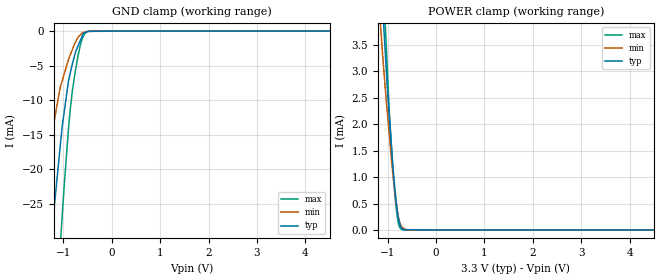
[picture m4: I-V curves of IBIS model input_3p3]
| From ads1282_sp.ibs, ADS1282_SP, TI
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|   input_3p3 Model
[Model]   input_3p3
Model_type   Input
Vinl = 0.66
Vinh = 2.64
|   typ   min   max
|   (nom PVT)   (Fast PVT)   (slow PVT)
|C_comp from frequency sweep method(F=4.1MHz)
|C_comp   3.666e-12   3.075e-12   4.204e-12
|C_comp from LC tank measurement(L=1nH)
|Resonant Frequency(Hz)   3.440e+09   3.460e+09   3.410e+09
C_comp   2.143e-12   2.118e-12   2.181e-12
| Where nom  PVT is Nominal Process,  3.3V,  25C
|   Fast PVT is Strong Process,   3.6V,  -40C
|   Slow PVT is Weak Process,   3V,  85C
[Model Spec]
Vinl   0.66   0.6   0.72
Vinh   2.64   2.4   2.88
[Voltage Range]   3.3   3   3.6
|Ambient Temperature   25   85   -40
|Junction Temperature
[Temperature Range]   25   85   -40
[Power Clamp Reference]   3.3   3   3.6
[GND Clamp Reference]   0   0   0
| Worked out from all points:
|   GND clamp passes 1 mA (typ) near -0.63 V on its own axis
|   POWER clamp passes 1 mA (typ) near -0.87 V on its own axis
[GND Clamp]
|   Voltage   I(typ)   I(min)   I(max)
-3.3V     -244.7mA   -167.1mA   -315mA
-1.617V   -63.98mA   -35.61mA   -98.6mA
-1.461V   -49.16mA   -26.24mA   -78.79mA
-1.245V   -30.03mA   -15.1mA    -52.22mA
-1.068V   -16.67mA   -8.14mA    -31.19mA
-1.03V    -13.93mA   -7.236mA   -26.98mA
-896.4mV  -7.217mA   -4.104mA   -14.12mA
-820.8mV  -4.87mA    -2.728mA   -8.903mA
-694.8mV  -2.061mA   -830.2uA   -3.406mA
-591mV    -373.4uA   -191.4uA   -745.7uA
-360mV    -37.09uA   -943.8nA   -522.5nA
6.6V      0A         0A         0A
[POWER Clamp]
|   Voltage   I(typ)   I(min)   I(max)
-3.3V     49.8mA     41.86mA    60.27mA
-1.152V   5.087mA    3.908mA    6.196mA
-1.089V   3.963mA    3.12mA     4.771mA
-1.048V   3.312mA    2.646mA    3.839mA
-1.035V   3.114mA    2.502mA    3.589mA
-968.4mV  2.164mA    1.821mA    2.266mA
-896.4mV  1.255mA    1.086mA    1.175mA
-871.2mV  980.7uA    879.6uA    875.5uA
-792mV    301uA      312uA      187.9uA
-712.8mV  32.54uA    63.77uA    8.168uA
-591mV    5.585uA    2.067uA    189.7nA
6.6V      0A         0A         0A
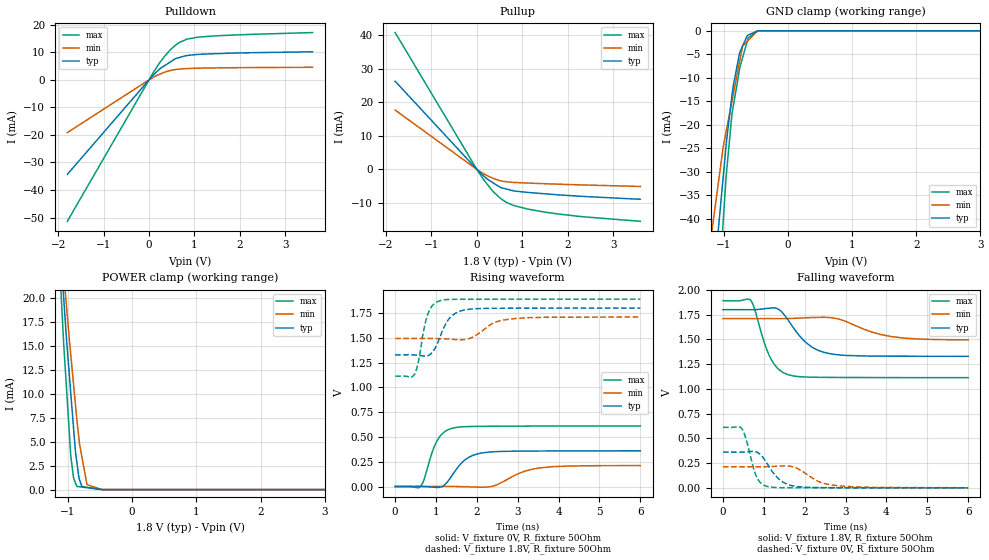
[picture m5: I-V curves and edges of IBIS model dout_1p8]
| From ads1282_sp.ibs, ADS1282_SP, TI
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|   dout_1p8 Model
[Model]   dout_1p8
Model_type   3-state
Polarity   Non-Inverting
Vmeas = 0.9
Vref = 0.9
Cref = 20pF
Rref = 50
|   typ   min   max
|   (nom PVT)   (Fast PVT)   (slow PVT)
|C_comp from frequency sweep method(F=4.1MHz)
C_comp   4.866e-12   3.817e-12   5.969e-12
|ON state : BUFFER OUTPUT TURNED HIGH
|C_comp   4.866e-12   3.817e-12   5.969e-12
|OFF state: BUFFER IN HIGH IMPEDANCE
|C_comp   4.612e-12   3.553e-12   5.679e-12
|C_comp from LC tank measurement(L=1nH)
|Resonant Frequency(Hz)   3.060e+09   3.240e+09   2.860e+09
|C_comp   2.708e-12   2.415e-12   3.100e-12
|ON state : BUFFER OUTPUT TURNED HIGH
|Resonant Frequency(Hz)   3.060e+09   3.240e+09   2.860e+09
|C_comp   2.708e-12   2.415e-12   3.100e-12
|OFF state: BUFFER IN HIGH IMPEDANCE
|Resonant Frequency(Hz)   3.100e+09   3.340e+09   2.870e+09
|C_comp   2.638e-12   2.273e-12   3.078e-12
| Where nom  PVT is Nominal Process,  1.8V,  25C
|   Fast PVT is Strong Process,   1.89V,  -40C
|   Slow PVT is Weak Process,   1.71V,  85C
[Voltage Range]   1.8   1.71   1.89
|Ambient Temperature   25   85   -40
|Junction Temperature
[Temperature Range]   25   85   -40
[Pullup Reference]   1.8   1.71   1.89
[Pulldown Reference]   0   0   0
[Power Clamp Reference]   1.8   1.71   1.89
[GND Clamp Reference]   0   0   0
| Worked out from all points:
|   slope of the pulldown table from 0 to 0.27 V, typ, clamps not added: 61.6 ohm
|   slope of the pullup table from 0 to 0.27 V, typ, clamps not added: 82.6 ohm
|   GND clamp passes 1 mA (typ) near -0.63 V on its own axis
|   POWER clamp passes 1 mA (typ) near -0.82 V on its own axis
|   falling waveform, V_fixture 1.8V, R_fixture 50Ohm: 20-80 % time 599ps typ, 910ps min, 397ps max; typ from 1.8 V to 1.33 V
|   rising waveform, V_fixture 0V, R_fixture 50Ohm: 20-80 % time 452ps typ, 686ps min, 321ps max; typ from 0 V to 0.36 V
|   rising waveform, V_fixture 1.8V, R_fixture 50Ohm: 20-80 % time 338ps typ, 497ps min, 222ps max; typ from 1.33 V to 1.8 V
|   falling waveform, V_fixture 0V, R_fixture 50Ohm: 20-80 % time 411ps typ, 556ps min, 244ps max; typ from 0.361 V to 0.001 V
[Pulldown]
|   Voltage   I(typ)   I(min)   I(max)
-1.8V     -34.32mA   -19.15mA   -51.35mA
107.7mV   1.937mA    1.049mA    3.036mA
252mV     4.192mA    2.177mA    6.588mA
332.6mV   5.052mA    2.713mA    8.353mA
451.7mV   6.321mA    3.316mA    10.59mA
574.6mV   7.631mA    3.732mA    12.46mA
667.2mV   8.107mA    3.886mA    13.56mA
835.4mV   8.812mA    4.089mA    14.78mA
1.089V    9.234mA    4.225mA    15.5mA
1.784V    9.681mA    4.391mA    16.21mA
3.6V      10.18mA    4.555mA    17.16mA
[GND Clamp]
|   Voltage   I(typ)   I(min)   I(max)
-1.8V     -174.4mA   -116.1mA   -255.2mA
-1.228V   -66.8mA    -47.38mA   -96.3mA
-1.105V   -45.8mA    -34.84mA   -64.56mA
-1.07V    -40.56mA   -31.23mA   -55.44mA
-1.005V   -31.06mA   -24.69mA   -40.45mA
-958.2mV  -24.08mA   -21.3mA    -30.74mA
-869.4mV  -13.74mA   -14.98mA   -17.71mA
-750.6mV  -4.735mA   -6.531mA   -8.173mA
-704.5mV  -3.283mA   -3.252mA   -5.744mA
-630mV    -987.2uA   -2.225mA   -2.174mA
-458.3mV  -20.05uA   -17.99uA   -22.38uA
3.6V      0A         0A         0A
[Pullup]
|   Voltage   I(typ)   I(min)   I(max)
-1.8V     26.3mA     17.69mA    40.8mA
0V        0A         0A         0A
139.9mV   -1.835mA   -1.206mA   -2.9mA
332.6mV   -3.8mA     -2.5mA     -6.214mA
502.7mV   -5.226mA   -3.313mA   -8.442mA
655.8mV   -5.863mA   -3.676mA   -9.859mA
801.4mV   -6.358mA   -3.868mA   -10.71mA
1.382V    -7.135mA   -4.203mA   -12.47mA
2.268V    -7.992mA   -4.603mA   -14.02mA
3.6V      -8.89mA    -5.079mA   -15.46mA
[POWER Clamp]
|   Voltage   I(typ)   I(min)   I(max)
-1.8V     87.36mA    77.13mA    101.7mA
-1.365V   49.31mA    46mA       53.95mA
-1.066V   20.03mA    22.59mA    15.23mA
-1.019V   15.4mA     18.9mA     10.24mA
-952.6mV  9.818mA    13.86mA    3.343mA
-912.9mV  6.472mA    11.02mA    1.23mA
-861.8mV  2.905mA    7.378mA    329.9uA
-820.8mV  1.04mA     4.853mA    295.3uA
-781.2mV  314.7uA    3.375mA    261.9uA
-702.8mV  235uA      516.8uA    195.8uA
-470.3mV  26.54nA    462.1nA    2.631nA
3.6V      0A         0A         0A
[Ramp]
R_load = 50
|   typ   min   max
dV/dt_r   0.215956/4.48764e-10   0.126791/6.81913e-10   0.366527/3.20304e-10
dV/dt_f   0.282717/5.98615e-10   0.129101/8.95175e-10   0.466066/3.95416e-10
[Falling Waveform]
V_fixture = 1.8V
V_fixture_min = 1.71V
V_fixture_max = 1.89V
R_fixture = 50Ohm
|   Time   V(typ)   V(min)   V(max)
0s        1.8V       1.71V      1.89V
670ps     1.799V     1.71V      1.899V
770ps     1.8V       1.71V      1.813V
1.162ns   1.816V     1.71V      1.313V
1.356ns   1.804V     1.71V      1.2V
1.6ns     1.691V     1.71V      1.143V
2.052ns   1.46V      1.718V     1.119V
2.602ns   1.357V     1.721V     1.116V
4.1ns     1.33V      1.529V     1.114V
6ns       1.329V     1.495V     1.113V
[Rising Waveform]
V_fixture = 0V
V_fixture_min = 0V
V_fixture_max = 0V
R_fixture = 50Ohm
|   Time   V(typ)   V(min)   V(max)
0s        552.4pV    690.8pV    457.1pV
618ps     548.2uV    14.16uV    1.117mV
700ps     103.6uV    41.05uV    61.6mV
1.026ns   -10.17mV   243.7uV    461.5mV
1.206ns   15.09mV    378.1uV    550.9mV
1.426ns   132.2mV    325.7uV    590mV
1.81ns    296.4mV    -3.345mV   604.9mV
2.248ns   345mV      -5.814mV   607.4mV
3.528ns   358mV      187.2mV    609.7mV
6ns       359.9mV    211.3mV    610.9mV
[Rising Waveform]
V_fixture = 1.8V
V_fixture_min = 1.71V
V_fixture_max = 1.89V
R_fixture = 50Ohm
|   Time   V(typ)   V(min)   V(max)
0s        1.328V     1.493V     1.113V
472ps     1.327V     1.493V     1.128V
566ps     1.323V     1.493V     1.253V
792ps     1.317V     1.493V     1.731V
1.096ns   1.504V     1.491V     1.874V
1.382ns   1.72V      1.485V     1.888V
1.756ns   1.785V     1.485V     1.888V
2.422ns   1.798V     1.652V     1.889V
2.928ns   1.798V     1.694V     1.889V
6ns       1.8V       1.709V     1.89V
[Falling Waveform]
V_fixture = 0V
V_fixture_min = 0V
V_fixture_max = 0V
R_fixture = 50Ohm
|   Time   V(typ)   V(min)   V(max)
0s        361.1mV    213.1mV    611.1mV
472ps     361.4mV    212.8mV    592.2mV
814ps     363.3mV    212.8mV    119.5mV
920ps     334.8mV    213.2mV    50.52mV
1.096ns   236.1mV    214.6mV    12.88mV
1.464ns   59.76mV    221.9mV    2.065mV
1.85ns    11.49mV    189.5mV    1.823mV
2.31ns    3.251mV    69.99mV    1.38mV
2.736ns   2.036mV    25.61mV    1.025mV
6ns       583.8uV    1.001mV    115.1uV
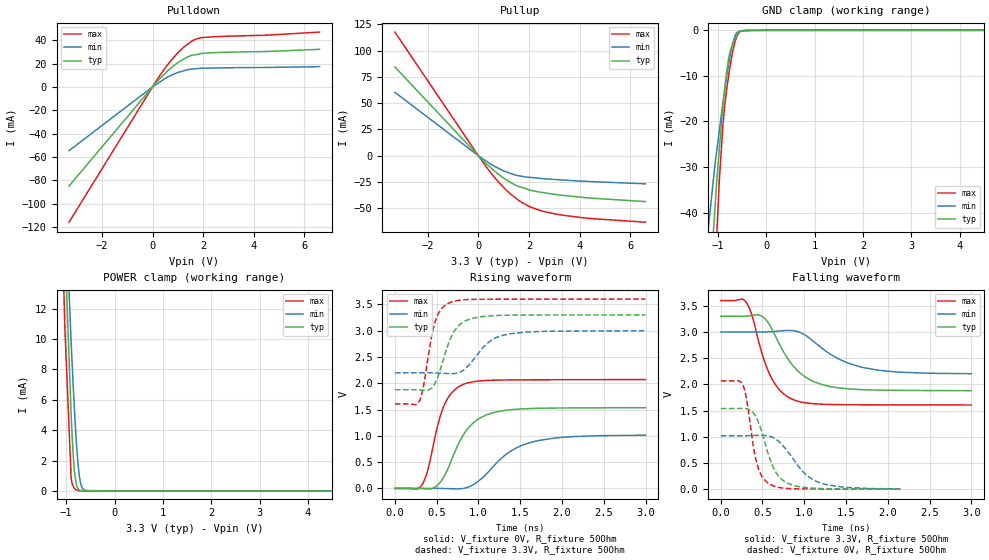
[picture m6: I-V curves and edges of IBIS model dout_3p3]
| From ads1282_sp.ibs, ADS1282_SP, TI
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|   dout_3p3 Model
[Model]   dout_3p3
Model_type   3-state
Polarity   Non-Inverting
Vmeas = 1.65
Vref = 1.65
Cref = 20pF
Rref = 50
|   typ   min   max
|   (nom PVT)   (Fast PVT)   (slow PVT)
|C_comp from frequency sweep method(F=4.1MHz)
C_comp   4.888e-12   4.336e-12   5.797e-12
|ON state : BUFFER OUTPUT TURNED HIGH
|C_comp   4.888e-12   4.336e-12   5.797e-12
|OFF state: BUFFER IN HIGH IMPEDANCE
|C_comp   4.296e-12   3.342e-12   5.283e-12
|C_comp from LC tank measurement(L=1nH)
|Resonant Frequency(Hz)   2.940e+09   3.040e+09   2.840e+09
|C_comp   2.933e-12   2.744e-12   3.144e-12
|ON state : BUFFER OUTPUT TURNED HIGH
|Resonant Frequency(Hz)   2.940e+09   3.040e+09   2.840e+09
|C_comp   2.933e-12   2.744e-12   3.144e-12
|OFF state: BUFFER IN HIGH IMPEDANCE
|Resonant Frequency   3.080e+09   3.290e+09   2.910e+09
|C_comp   2.673e-12   2.343e-12   2.994e-12
| Where nom  PVT is Nominal Process,  3.3V,  25C
|   Fast PVT is Strong Process,   3.6V,  -40C
|   Slow PVT is Weak Process,   3V,  85C
[Voltage Range]   3.3   3   3.6
|Ambient Temperature   25   85   -40
|Junction Temperature
[Temperature Range]   25   85   -40
[Pullup Reference]   3.3   3   3.6
[Pulldown Reference]   0   0   0
[Power Clamp Reference]   3.3   3   3.6
[GND Clamp Reference]   0   0   0
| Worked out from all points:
|   slope of the pulldown table from 0 to 0.495 V, typ, clamps not added: 43.1 ohm
|   slope of the pullup table from 0 to 0.495 V, typ, clamps not added: 43.1 ohm
|   GND clamp passes 1 mA (typ) near -0.61 V on its own axis
|   POWER clamp passes 1 mA (typ) near -0.82 V on its own axis
|   falling waveform, V_fixture 3.3V, R_fixture 50Ohm: 20-80 % time 368ps typ, 518ps min, 256ps max; typ from 3.3 V to 1.88 V
|   rising waveform, V_fixture 0V, R_fixture 50Ohm: 20-80 % time 311ps typ, 459ps min, 208ps max; typ from 0 V to 1.53 V
|   rising waveform, V_fixture 3.3V, R_fixture 50Ohm: 20-80 % time 198ps typ, 284ps min, 140ps max; typ from 1.88 V to 3.3 V
|   falling waveform, V_fixture 0V, R_fixture 50Ohm: 20-80 % time 203ps typ, 325ps min, 131ps max; typ from 1.54 V to 0.006 V
[Pulldown]
|   Voltage   I(typ)   I(min)   I(max)
-3.3V     -84.83mA   -54.6mA    -115.8mA
172.8mV   4.34mA     2.512mA    5.975mA
651.6mV   14.72mA    9.067mA    20.52mA
939.6mV   19.77mA    11.85mA    27.79mA
1.246V    24.05mA    13.85mA    34.24mA
1.57V     27.12mA    15.31mA    39.44mA
1.876V    28.48mA    16mA       42mA
4.5V      30.27mA    16.64mA    44.23mA
6.6V      32.15mA    17.33mA    46.89mA
[GND Clamp]
|   Voltage   I(typ)   I(min)   I(max)
-3.3V     -482.3mA   -336.3mA   -681.8mA
-1.236V   -68.04mA   -47.36mA   -99.36mA
-1.181V   -58.37mA   -41.82mA   -84.99mA
-1.062V   -39.36mA   -29.7mA    -53.56mA
-1.02V    -32.63mA   -26.19mA   -44.06mA
-896.4mV  -16.56mA   -15.93mA   -20.92mA
-820.8mV  -9.326mA   -10.41mA   -13.14mA
-745.8mV  -4.504mA   -5.626mA   -7.828mA
-699mV    -3.288mA   -3.004mA   -4.984mA
-612mV    -1.028mA   -589.9uA   -1.397mA
-546mV    -211.8uA   -139.2uA   -372.2uA
6.6V      0A         0A         0A
[Pullup]
|   Voltage   I(typ)   I(min)   I(max)
-3.3V     84.43mA    60.29mA    117.5mA
172.8mV   -4.272mA   -2.827mA   -6.008mA
586.8mV   -13.46mA   -9.375mA   -19.1mA
939.6mV   -20.19mA   -13.7mA    -28.71mA
1.246V    -24.99mA   -16.53mA   -35.81mA
1.588V    -29.1mA    -18.97mA   -42.32mA
2.167V    -33.36mA   -20.84mA   -49.72mA
3.089V    -36.92mA   -22.65mA   -55.5mA
4.496V    -40.34mA   -24.57mA   -59.74mA
6.6V      -43.54mA   -26.68mA   -63.12mA
[POWER Clamp]
|   Voltage   I(typ)   I(min)   I(max)
-3.3V     137.9mA    127.7mA    153.3mA
-1.429V   54.72mA    50.46mA    62.04mA
-1.03V    16.43mA    19.9mA     10.89mA
-896.4mV  4.917mA    9.718mA    783.4uA
-844.8mV  1.905mA    6.31mA     249.9uA
-825mV    1.165mA    5.096mA    152.8uA
-792mV    443.4uA    3.321mA    70.08uA
-753mV    128.6uA    1.694mA    27.67uA
-705mV    30.69uA    548uA      7.83uA
-672mV    29.24uA    215.6uA    3.533uA
-591mV    25.7uA     18.13uA    579.7nA
6.6V      0A         0A         0A
[Ramp]
R_load = 50
|   typ   min   max
dV/dt_r   0.920399/3.10317e-10   0.606912/4.57513e-10   1.24136/2.0762e-10
dV/dt_f   0.851018/3.67713e-10   0.477424/5.09929e-10   1.19509/2.55084e-10
[Falling Waveform]
V_fixture = 3.3V
V_fixture_min = 3V
V_fixture_max = 3.6V
R_fixture = 50Ohm
|   Time   V(typ)   V(min)   V(max)
0s        3.3V       3V         3.6V
304ps     3.303V     3V         3.571V
376ps     3.317V     2.999V     3.308V
468ps     3.319V     2.999V     2.736V
588ps     3.127V     3.005V     2.185V
708ps     2.749V     3.019V     1.889V
868ps     2.352V     3.025V     1.71V
1.212ns   1.997V     2.69V      1.623V
1.68ns    1.901V     2.33V      1.612V
2.998ns   1.882V     2.204V     1.608V
[Rising Waveform]
V_fixture = 0V
V_fixture_min = 0V
V_fixture_max = 0V
R_fixture = 50Ohm
|   Time   V(typ)   V(min)   V(max)
0s        861.4pV    1.004nV    776.1pV
320ps     -1.765mV   325.3uV    57.59mV
396ps     -8.332mV   529.5uV    359.8mV
506ps     52.51mV    145.2uV    1.159V
580ps     204mV      -1.125mV   1.543V
814ps     1.004V     -321.9uV   1.974V
1.098ns   1.398V     278.5mV    2.052V
1.336ns   1.487V     653mV      2.061V
1.612ns   1.518V     868.9mV    2.064V
2.998ns   1.534V     1.012V     2.069V
[Rising Waveform]
V_fixture = 3.3V
V_fixture_min = 3V
V_fixture_max = 3.6V
R_fixture = 50Ohm
|   Time   V(typ)   V(min)   V(max)
0s        1.876V     2.197V     1.606V
296ps     1.871V     2.198V     1.668V
338ps     1.866V     2.198V     1.913V
478ps     1.991V     2.195V     3.148V
552ps     2.306V     2.19V      3.404V
646ps     2.772V     2.182V     3.524V
848ps     3.188V     2.283V     3.588V
1.088ns   3.274V     2.733V     3.595V
1.302ns   3.29V      2.914V     3.596V
2.998ns   3.298V     2.998V     3.599V
[Falling Waveform]
V_fixture = 0V
V_fixture_min = 0V
V_fixture_max = 0V
R_fixture = 50Ohm
|   Time   V(typ)   V(min)   V(max)
0s        1.54V      1.022V     2.068V
260ps     1.543V     1.022V     2.014V
308ps     1.538V     1.023V     1.728V
386ps     1.468V     1.026V     859.3mV
430ps     1.356V     1.028V     510mV
576ps     637.8mV    1.017V     108.4mV
650ps     351.4mV    966.7mV    55.29mV
756ps     158.5mV    812mV      22.11mV
1.142ns   18.54mV    154mV      6.832mV
2.148ns   5.882mV    8.207mV    3.094mV
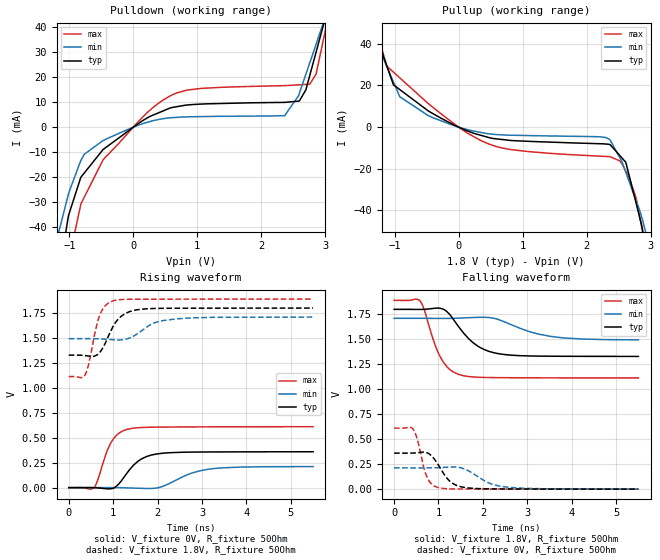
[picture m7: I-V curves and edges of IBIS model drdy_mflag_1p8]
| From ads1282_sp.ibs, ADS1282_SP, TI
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|   drdy_mflag_1p8 Model
[Model]   drdy_mflag_1p8
Model_type   Output
Polarity   Non-Inverting
Vmeas = 0.9
Vref = 0.9
Cref = 10pF
Rref = 50
|   typ   min   max
|   (nom PVT)   (Fast PVT)   (slow PVT)
|C_comp from frequency sweep method(F=4.1MHz)
C_comp   4.866e-12   3.817e-12   5.969e-12
|ON state : BUFFER OUTPUT TURNED HIGH
|C_comp   4.866e-12   3.817e-12   5.969e-12
|OFF state: BUFFER OUTPUT TURNED LOW
|C_comp   5.126e-12   4.022e-12   6.109e-12
|C_comp from LC tank measurement(L=1nH)
|Resonant Frequency(Hz)   3.060e+09   3.240e+09   2.860e+09
|C_comp   2.708e-12   2.415e-12   3.100e-12
|ON state : BUFFER OUTPUT TURNED HIGH
|Resonant Frequency(Hz)   3.060e+09   3.240e+09   2.860e+09
|C_comp   2.708e-12   2.415e-12   3.100e-12
|OFF state: BUFFER IN HIGH IMPEDANCE
|Resonant Frequency(Hz)   3.090e+09   3.260e+09   2.870e+09
|C_comp   2.656e-12   2.386e-12   3.078e-12
| Where nom  PVT is Nominal Process,  1.8V,  25C
|   Fast PVT is Strong Process,   1.89V,  -40C
|   Slow PVT is Weak Process,   1.71V,  85C
[Voltage Range]   1.8   1.71   1.89
|Ambient Temperature   25   85   -40
|Junction Temperature
[Temperature Range]   25   85   -40
[Pullup Reference]   1.8   1.71   1.89
[Pulldown Reference]   0   0   0
[Power Clamp Reference]   1.8   1.71   1.89
[GND Clamp Reference]   0   0   0
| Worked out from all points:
|   slope of the pulldown table from 0 to 0.27 V, typ, clamps not added: 61.6 ohm
|   slope of the pullup table from 0 to 0.27 V, typ, clamps not added: 82.6 ohm
|   falling waveform, V_fixture 1.8V, R_fixture 50Ohm: 20-80 % time 593ps typ, 897ps min, 392ps max; typ from 1.8 V to 1.33 V
|   rising waveform, V_fixture 0V, R_fixture 50Ohm: 20-80 % time 448ps typ, 684ps min, 320ps max; typ from 0 V to 0.36 V
|   rising waveform, V_fixture 1.8V, R_fixture 50Ohm: 20-80 % time 357ps typ, 510ps min, 240ps max; typ from 1.33 V to 1.8 V
|   falling waveform, V_fixture 0V, R_fixture 50Ohm: 20-80 % time 349ps typ, 526ps min, 211ps max; typ from 0.361 V to 0.001 V
[Pulldown]
|   Voltage   I(typ)   I(min)   I(max)
-1.8V     -174.9mA   -116.4mA   -255.8mA
-1.298V   -80.36mA   -55.08mA   -117.1mA
-1.072V   -44.46mA   -32.5mA    -63.24mA
-1.005V   -34.67mA   -25.94mA   -52.67mA
-766.1mV  -18.28mA   -10.81mA   -27.91mA
-471.6mV  -8.891mA   -5.329mA   -12.98mA
574.6mV   7.631mA    3.732mA    12.46mA
2.365V    9.876mA    4.589mA    16.56mA
2.594V    10.41mA    13.41mA    16.89mA
2.856V    29.92mA    33.05mA    21.19mA
3.42V     83.17mA    75.35mA    88.89mA
3.6V      97.54mA    88.85mA    110.5mA
[Pullup]
|   Voltage   I(typ)   I(min)   I(max)
-1.8V     87.83mA    77.65mA    102.3mA
-1.123V   29.42mA    29.13mA    29.29mA
-1.019V   20.3mA     21.69mA    26.41mA
-920mV    18.03mA    14.62mA    23.67mA
-470.3mV  7.7mA      5.423mA    11.19mA
591.6mV   -5.634mA   -3.565mA   -9.333mA
2.362V    -8.32mA    -5.979mA   -14.18mA
2.612V    -16.85mA   -21.65mA   -21.09mA
2.778V    -37.12mA   -35.72mA   -34.55mA
2.871V    -48.82mA   -44.24mA   -49.96mA
3.117V    -91.16mA   -73.66mA   -110.8mA
3.6V      -183.3mA   -131.6mA   -245.2mA
[Ramp]
R_load = 50
|   typ   min   max
dV/dt_r   0.215852/4.47249e-10   0.126732/6.8335e-10   0.366473/3.18763e-10
dV/dt_f   0.282649/5.92374e-10   0.129173/8.83014e-10   0.466024/3.91539e-10
[Falling Waveform]
V_fixture = 1.8V
V_fixture_min = 1.71V
V_fixture_max = 1.89V
R_fixture = 50Ohm
|   Time   V(typ)   V(min)   V(max)
0s        1.8V       1.71V      1.89V
576ps     1.799V     1.71V      1.889V
672ps     1.8V       1.71V      1.806V
1.044ns   1.81V      1.71V      1.322V
1.232ns   1.759V     1.709V     1.207V
1.468ns   1.618V     1.712V     1.147V
1.886ns   1.432V     1.72V      1.121V
2.324ns   1.359V     1.702V     1.117V
3.524ns   1.331V     1.53V      1.114V
5.5ns     1.329V     1.495V     1.113V
[Rising Waveform]
V_fixture = 0V
V_fixture_min = 0V
V_fixture_max = 0V
R_fixture = 50Ohm
|   Time   V(typ)   V(min)   V(max)
0s        552.4pV    690.8pV    457.1pV
572ps     -259.3uV   226.6uV    -280.6uV
960ps     -10.03mV   535.2uV    457.7mV
1.12ns    34.61mV    49.16uV    542.5mV
1.336ns   160.9mV    -2.648mV   586.6mV
1.64ns    288.4mV    -7.082mV   602.7mV
2.064ns   342.4mV    5.281mV    606.8mV
2.722ns   355.9mV    138.5mV    608.6mV
3.166ns   357.6mV    185.9mV    609.3mV
5.5ns     359.8mV    211.2mV    610.8mV
[Rising Waveform]
V_fixture = 1.8V
V_fixture_min = 1.71V
V_fixture_max = 1.89V
R_fixture = 50Ohm
|   Time   V(typ)   V(min)   V(max)
0s        1.328V     1.493V     1.113V
362ps     1.324V     1.493V     1.126V
446ps     1.319V     1.493V     1.233V
696ps     1.354V     1.491V     1.726V
818ps     1.444V     1.488V     1.822V
998ps     1.617V     1.483V     1.872V
1.278ns   1.746V     1.487V     1.887V
1.72ns    1.791V     1.598V     1.888V
2.452ns   1.798V     1.692V     1.889V
5.5ns     1.8V       1.709V     1.89V
[Falling Waveform]
V_fixture = 0V
V_fixture_min = 0V
V_fixture_max = 0V
R_fixture = 50Ohm
|   Time   V(typ)   V(min)   V(max)
0s        361.1mV    213.1mV    611.1mV
424ps     361.6mV    212.7mV    603.9mV
522ps     364.5mV    212.6mV    500.4mV
738ps     364.4mV    212.9mV    125mV
1.006ns   236mV      215.8mV    14.54mV
1.254ns   80.14mV    221.9mV    3.041mV
1.652ns   13.35mV    189.4mV    1.974mV
2.096ns   3.54mV     69.86mV    1.542mV
2.478ns   2.199mV    24.21mV    1.18mV
5.5ns     669.4uV    1.06mV     154.7uV
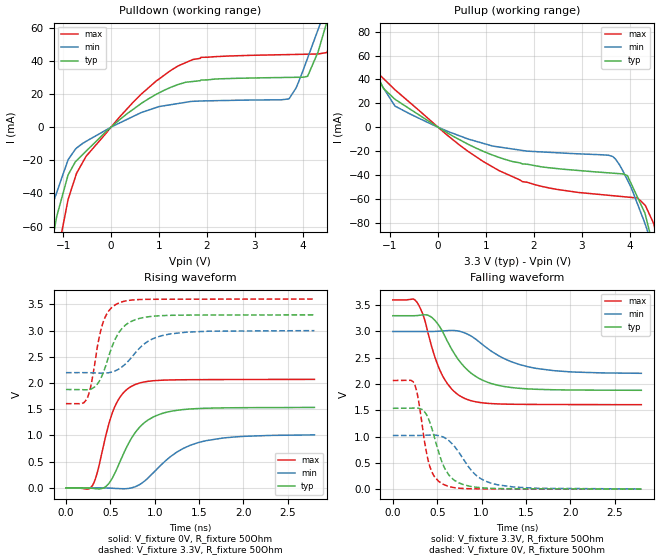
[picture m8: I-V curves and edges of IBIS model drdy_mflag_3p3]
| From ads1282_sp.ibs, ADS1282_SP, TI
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|   drdy_mflag_3p3 Model
[Model]   drdy_mflag_3p3
Model_type   Output
Polarity   Non-Inverting
Vmeas = 1.65
Vref = 1.65
Cref = 10pF
Rref = 50
|   typ   min   max
|   (nom PVT)   (Fast PVT)   (slow PVT)
|C_comp from frequency sweep method(F=4.1MHz)
|C_comp   4.888e-12   4.336e-12   5.797e-12
|ON state : BUFFER OUTPUT TURNED HIGH
|C_comp   4.888e-12   4.336e-12   5.797e-12
|OFF state: BUFFER OUTPUT TURNED LOW
|C_comp   4.644e-12   3.666e-12   5.651e-12
|C_comp from LC tank measurement(L=1nH)
|Resonant Frequency(Hz)   2.940e+09   3.040e+09   2.840e+09
C_comp   2.933e-12   2.744e-12   3.144e-12
|ON state : BUFFER OUTPUT TURNED HIGH
|Resonant Frequency(Hz)   2.940e+09   3.040e+09   2.840e+09
|C_comp   2.933e-12   2.744e-12   3.144e-12
|OFF state: BUFFER IN HIGH IMPEDANCE
|Resonant Frequency(Hz)   3.030e+09   3.150e+09   2.900e+09
|C_comp   2.762e-12   2.555e-12   3.015e-12
| Where nom  PVT is Nominal Process,  3.3V,  25C
|   Fast PVT is Strong Process,   3.6V,  -40C
|   Slow PVT is Weak Process,   3V,  85C
[Voltage Range]   3.3   3   3.6
|Ambient Temperature   25   85   -40
|Junction Temperature
[Temperature Range]   25   85   -40
[Pullup Reference]   3.3   3   3.6
[Pulldown Reference]   0   0   0
[Power Clamp Reference]   3.3   3   3.6
[GND Clamp Reference]   0   0   0
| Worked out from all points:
|   slope of the pulldown table from 0 to 0.495 V, typ, clamps not added: 43.1 ohm
|   slope of the pullup table from 0 to 0.495 V, typ, clamps not added: 43.1 ohm
|   falling waveform, V_fixture 3.3V, R_fixture 50Ohm: 20-80 % time 362ps typ, 500ps min, 253ps max; typ from 3.3 V to 1.88 V
|   rising waveform, V_fixture 0V, R_fixture 50Ohm: 20-80 % time 315ps typ, 463ps min, 211ps max; typ from 0 V to 1.53 V
|   rising waveform, V_fixture 3.3V, R_fixture 50Ohm: 20-80 % time 207ps typ, 306ps min, 141ps max; typ from 1.88 V to 3.3 V
|   falling waveform, V_fixture 0V, R_fixture 50Ohm: 20-80 % time 191ps typ, 291ps min, 128ps max; typ from 1.54 V to 0.004 V
[Pulldown]
|   Voltage   I(typ)   I(min)   I(max)
-3.3V     -482.6mA   -335mA     -682.1mA
-1.343V   -88.53mA   -61.49mA   -129.7mA
-1.13V    -53.58mA   -39.18mA   -78.54mA
-745.8mV  -20.97mA   -13.4mA    -30.17mA
-132mV    -3.393mA   -2.184mA   -4.631mA
1.706V    27.55mA    15.57mA    40.81mA
3.711V    30.01mA    17.16mA    43.8mA
4.099V    30.68mA    41.7mA     44.02mA
4.316V    45.38mA    58.87mA    44.14mA
4.468V    60.38mA    70.41mA    44.87mA
4.739V    87.08mA    86.95mA    68.98mA
6.6V      170mA      149.5mA    197.8mA
[Pullup]
|   Voltage   I(typ)   I(min)   I(max)
-3.3V     137.9mA    127.5mA    153.4mA
-2.073V   104.5mA    92.17mA    121.2mA
-1.756V   84.9mA     72.07mA    98.48mA
-1.139V   32.61mA    32.99mA    40.82mA
-897.6mV  23.39mA    17.73mA    31.39mA
633.6mV   -14.47mA   -10.03mA   -20.46mA
1.76V     -30.79mA   -19.54mA   -45.68mA
3.642V    -38.58mA   -24.6mA    -57.47mA
3.95V     -40.57mA   -44.23mA   -58.63mA
4.331V    -74.44mA   -82.43mA   -66.2mA
4.468V    -96.44mA   -98.91mA   -78.2mA
6.6V      -525.8mA   -407.1mA   -659.6mA
[Ramp]
R_load = 50
|   typ   min   max
dV/dt_r   0.920116/3.13971e-10   0.606451/4.61826e-10   1.24118/2.10711e-10
dV/dt_f   0.850783/3.6116e-10   0.477211/4.99021e-10   1.19492/2.52672e-10
[Falling Waveform]
V_fixture = 3.3V
V_fixture_min = 3V
V_fixture_max = 3.6V
R_fixture = 50Ohm
|   Time   V(typ)   V(min)   V(max)
0s        3.3V       3V         3.6V
272ps     3.303V     3V         3.556V
352ps     3.317V     2.999V     3.26V
431ps     3.278V     3V         2.753V
553ps     3.022V     3.009V     2.183V
672ps     2.637V     3.02V      1.89V
815ps     2.31V      2.97V      1.723V
1.076ns   2.03V      2.667V     1.633V
1.518ns   1.909V     2.331V     1.614V
2.8ns     1.882V     2.205V     1.608V
[Rising Waveform]
V_fixture = 0V
V_fixture_min = 0V
V_fixture_max = 0V
R_fixture = 50Ohm
|   Time   V(typ)   V(min)   V(max)
0s        861.4pV    1.004nV    776.1pV
298ps     -7.525mV   975.2uV    44.31mV
363ps     -17.86mV   911.3uV    356.7mV
440ps     15.28mV    -1.042mV   932.8mV
545ps     262mV      -8.349mV   1.527V
639ps     614.3mV    -15.17mV   1.797V
778ps     1.049V     21.13mV    1.969V
1.07ns    1.412V     434.2mV    2.052V
1.484ns   1.513V     860.3mV    2.063V
2.8ns     1.534V     1.011V     2.069V
[Rising Waveform]
V_fixture = 3.3V
V_fixture_min = 3V
V_fixture_max = 3.6V
R_fixture = 50Ohm
|   Time   V(typ)   V(min)   V(max)
0s        1.876V     2.197V     1.606V
233ps     1.87V      2.197V     1.686V
278ps     1.882V     2.195V     1.923V
368ps     2.013V     2.189V     2.815V
418ps     2.185V     2.187V     3.152V
497ps     2.587V     2.2V       3.404V
603ps     2.977V     2.273V     3.529V
912ps     3.258V     2.781V     3.594V
1.165ns   3.289V     2.931V     3.596V
2.8ns     3.298V     2.998V     3.599V
[Falling Waveform]
V_fixture = 0V
V_fixture_min = 0V
V_fixture_max = 0V
R_fixture = 50Ohm
|   Time   V(typ)   V(min)   V(max)
0s        1.54V      1.022V     2.068V
239ps     1.544V     1.022V     2.019V
284ps     1.541V     1.023V     1.741V
359ps     1.468V     1.027V     889.9mV
412ps     1.296V     1.03V      459.4mV
577ps     425.7mV    985.4mV    87.14mV
746ps     120.3mV    698.3mV    20.2mV
933ps     40.01mV    273.9mV    8.805mV
1.104ns   17.86mV    117.2mV    6.986mV
2.8ns     4.413mV    5.372mV    1.881mV
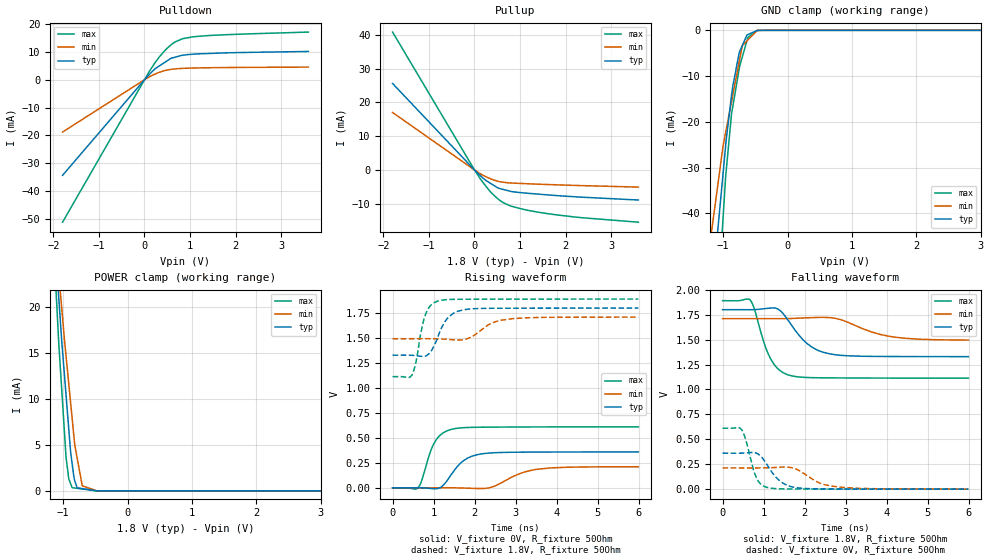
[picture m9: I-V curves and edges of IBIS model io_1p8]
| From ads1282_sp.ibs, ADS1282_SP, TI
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|   io_1p8 Model
[Model]   io_1p8
Model_type   I/O
Polarity   Non-Inverting
Enable   Active-Low
Vinl = 0.36
Vinh = 1.44
Vmeas = 0.9
Vref = 0.9
Cref = 20pF
Rref = 50
|   typ   min   max
|   (nom PVT)   (Fast PVT)   (slow PVT)
|C_comp from frequency method(4.1MHz)
|Average
C_comp   4.869e-12   3.785e-12   5.989e-12
|ON state : BUFFER OUTPUT TURNED HIGH
|C_comp   4.996e-12   3.917e-12   6.134e-12
|OFF state: BUFFER IN HIGH IMPEDANCE
|C_comp   4.742e-12   3.652e-12   5.844e-12
|C_comp from LC tank measurement(L=1nH)
|Average
|Resonant Frequency(Hz)   3.010e+09   3.200e+09   2.815e+09
|C_comp   2.799e-12   2.478e-12   3.200e-12
|ON state : BUFFER OUTPUT TURNED HIGH
|Resonant Frequency(Hz)   2.990e+09   3.150e+09   2.810e+09
|C_comp   2.836e-12   2.555e-12   3.211e-12
|OFF state: BUFFER IN HIGH IMPEDANCE
|Resonant Frequency(Hz)   3.030e+09   3.250e+09   2.820e+09
|C_comp   2.762e-12   2.401e-12   3.188e-12
| Where nom  PVT is Nominal Process,  1.8V,  25C
|   Fast PVT is Strong Process,   1.89V,  -40C
|   Slow PVT is Weak Process,   1.71V,  85C
[Model Spec]
Vinl   0.36   0.342   0.378
Vinh   1.44   1.368   1.512
[Voltage Range]   1.8   1.71   1.89
|Ambient Temperature   25   85   -40
|Junction Temperature
[Temperature Range]   25   85   -40
[Pullup Reference]   1.8   1.71   1.89
[Pulldown Reference]   0   0   0
[Power Clamp Reference]   1.8   1.71   1.89
[GND Clamp Reference]   0   0   0
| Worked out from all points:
|   slope of the pulldown table from 0 to 0.27 V, typ, clamps not added: 61.6 ohm
|   slope of the pullup table from 0 to 0.27 V, typ, clamps not added: 82.6 ohm
|   GND clamp passes 1 mA (typ) near -0.63 V on its own axis
|   POWER clamp passes 1 mA (typ) near -0.82 V on its own axis
|   falling waveform, V_fixture 1.8V, R_fixture 50Ohm: 20-80 % time 606ps typ, 917ps min, 402ps max; typ from 1.8 V to 1.33 V
|   rising waveform, V_fixture 0V, R_fixture 50Ohm: 20-80 % time 462ps typ, 695ps min, 331ps max; typ from 0 V to 0.36 V
|   rising waveform, V_fixture 1.8V, R_fixture 50Ohm: 20-80 % time 346ps typ, 506ps min, 227ps max; typ from 1.33 V to 1.8 V
|   falling waveform, V_fixture 0V, R_fixture 50Ohm: 20-80 % time 419ps typ, 572ps min, 249ps max; typ from 0.361 V to 0.001 V
[Pulldown]
|   Voltage   I(typ)   I(min)   I(max)
-1.8V     -34.41mA   -18.82mA   -51.27mA
107.7mV   1.937mA    1.049mA    3.036mA
252mV     4.192mA    2.177mA    6.588mA
332.6mV   5.052mA    2.713mA    8.353mA
451.7mV   6.321mA    3.316mA    10.59mA
574.6mV   7.631mA    3.732mA    12.46mA
667.2mV   8.107mA    3.886mA    13.56mA
835.4mV   8.812mA    4.089mA    14.78mA
1.089V    9.234mA    4.225mA    15.5mA
1.784V    9.681mA    4.391mA    16.21mA
3.6V      10.18mA    4.555mA    17.16mA
[GND Clamp]
|   Voltage   I(typ)   I(min)   I(max)
-1.8V     -177.9mA   -119.4mA   -259.1mA
-1.23V    -68.68mA   -49.16mA   -98.35mA
-1.105V   -46.94mA   -36.09mA   -65.66mA
-1.072V   -41.87mA   -32.59mA   -56.89mA
-1.002V   -31.37mA   -25.33mA   -41.16mA
-960.1mV  -25.03mA   -22.23mA   -31.79mA
-869.4mV  -14.15mA   -15.57mA   -18.2mA
-750.6mV  -4.899mA   -6.855mA   -8.42mA
-702.8mV  -3.343mA   -3.348mA   -5.836mA
-630mV    -1.022mA   -2.308mA   -2.244mA
-458.3mV  -20.73uA   -18.65uA   -23.13uA
3.6V      0A         0A         0A
[Pullup]
|   Voltage   I(typ)   I(min)   I(max)
-1.8V     25.59mA    17.01mA    40.8mA
0V        0A         0A         0A
139.9mV   -1.835mA   -1.206mA   -2.9mA
332.6mV   -3.8mA     -2.5mA     -6.214mA
502.7mV   -5.226mA   -3.313mA   -8.442mA
655.8mV   -5.863mA   -3.676mA   -9.859mA
801.4mV   -6.358mA   -3.868mA   -10.71mA
1.382V    -7.135mA   -4.203mA   -12.47mA
2.268V    -7.992mA   -4.603mA   -14.02mA
3.6V      -8.89mA    -5.079mA   -15.46mA
[POWER Clamp]
|   Voltage   I(typ)   I(min)   I(max)
-1.8V     90.6mA     80.07mA    105.3mA
-1.366V   51.05mA    47.59mA    55.94mA
-1.068V   20.91mA    23.53mA    16mA
-1.019V   15.96mA    19.57mA    10.63mA
-952.6mV  10.19mA    14.46mA    3.505mA
-912.9mV  6.73mA     11.63mA    1.314mA
-859.9mV  2.938mA    7.853mA    349.3uA
-819.1mV  1.066mA    4.961mA    312.7uA
-781.2mV  336.9uA    3.523mA    278.7uA
-702.8mV  251.6uA    547.7uA    208.3uA
-470.3mV  29.97nA    502.3nA    2.97nA
3.6V      0A         0A         0A
[Ramp]
R_load = 50
|   typ   min   max
dV/dt_r   0.21595/4.58579e-10   0.126777/6.9315e-10   0.366518/3.30612e-10
dV/dt_f   0.282711/6.05496e-10   0.129066/9.01902e-10   0.466064/4.00584e-10
[Falling Waveform]
V_fixture = 1.8V
V_fixture_min = 1.71V
V_fixture_max = 1.89V
R_fixture = 50Ohm
|   Time   V(typ)   V(min)   V(max)
0s        1.8V       1.71V      1.89V
668ps     1.799V     1.71V      1.9V
772ps     1.8V       1.71V      1.812V
1.156ns   1.816V     1.71V      1.32V
1.356ns   1.804V     1.71V      1.205V
1.604ns   1.691V     1.71V      1.145V
2.064ns   1.459V     1.718V     1.12V
2.608ns   1.357V     1.72V      1.116V
4.108ns   1.33V      1.53V      1.114V
5.996ns   1.329V     1.495V     1.113V
[Rising Waveform]
V_fixture = 0V
V_fixture_min = 0V
V_fixture_max = 0V
R_fixture = 50Ohm
|   Time   V(typ)   V(min)   V(max)
0s        644.5pV    805.2pV    533.3pV
616ps     540.5uV    13.08uV    159.4uV
700ps     107.4uV    39.99uV    60.04mV
1.032ns   -10.09mV   244uV      459.9mV
1.216ns   18.17mV    380.9uV    545.2mV
1.448ns   141.9mV    256.5uV    587mV
1.816ns   294.6mV    -3.364mV   603.9mV
2.252ns   344mV      -5.641mV   607.2mV
3.54ns    357.9mV    186.7mV    609.7mV
5.996ns   359.9mV    211.3mV    610.9mV
[Rising Waveform]
V_fixture = 1.8V
V_fixture_min = 1.71V
V_fixture_max = 1.89V
R_fixture = 50Ohm
|   Time   V(typ)   V(min)   V(max)
0s        1.328V     1.493V     1.113V
472ps     1.327V     1.493V     1.128V
568ps     1.323V     1.493V     1.254V
796ps     1.318V     1.493V     1.727V
1.104ns   1.509V     1.491V     1.869V
1.388ns   1.718V     1.485V     1.886V
1.764ns   1.784V     1.486V     1.888V
2.428ns   1.798V     1.651V     1.889V
2.94ns    1.798V     1.694V     1.889V
5.996ns   1.8V       1.709V     1.89V
[Falling Waveform]
V_fixture = 0V
V_fixture_min = 0V
V_fixture_max = 0V
R_fixture = 50Ohm
|   Time   V(typ)   V(min)   V(max)
0s        361.1mV    213.1mV    611.1mV
472ps     361.4mV    212.8mV    592.7mV
556ps     363.2mV    212.7mV    507.2mV
820ps     362.3mV    212.8mV    120.2mV
1.1ns     236.2mV    214.6mV    16.12mV
1.472ns   60.86mV    222mV      2.867mV
1.852ns   12.14mV    189.8mV    1.858mV
2.32ns    3.297mV    70.3mV     1.376mV
2.772ns   2.013mV    25.02mV    1.006mV
5.996ns   587.2uV    1.007mV    116.6uV
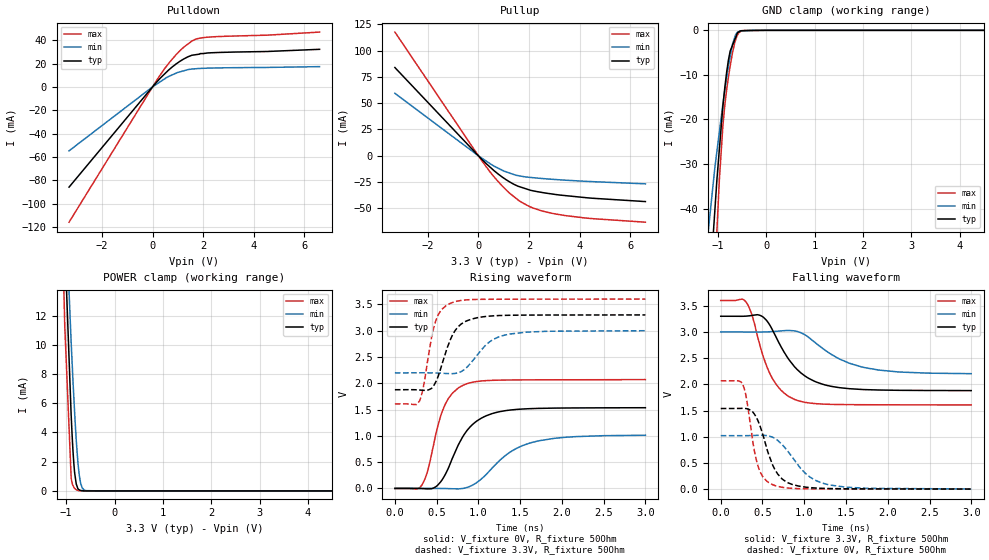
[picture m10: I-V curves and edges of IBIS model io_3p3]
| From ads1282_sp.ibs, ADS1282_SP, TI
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|   io_3p3 Model
[Model]   io_3p3
Model_type   I/O
Polarity   Non-Inverting
Enable   Active-Low
Vinl = 0.66
Vinh = 2.64
Vmeas = 1.65
Vref = 1.65
Cref = 20pF
Rref = 50
|   typ   min   max
|   (nom PVT)   (Fast PVT)   (slow PVT)
|C_comp from frequency method(4.1MHz)
|Average
C_comp   4.711e-12   3.970e-12   5.731e-12
|OFF state: BUFFER IN HIGH IMPEDANCE
|C_comp   5.007e-12   4.467e-12   5.988e-12
|ON state : BUFFER OUTPUT TURNED HIGH
|C_comp   4.415e-12   3.474e-12   5.474e-12
|C_comp from LC tank measurement(L=1nH)
|Average
|Resonant Frequency(Hz)   2.940e+09   3.080e+09   2.820e+09
|C_comp   2.939e-12   2.685e-12   3.191e-12
|ON state : BUFFER OUTPUT TURNED HIGH
|Resonant Frequency(Hz)   2.870e+09   2.960e+09   2.780e+09
|C_comp   3.078e-12   2.894e-12   3.281e-12
|OFF state: BUFFER IN HIGH IMPEDANCE
|Resonant Frequency(Hz)   3.010e+09   3.200e+09   2.860e+09
|C_comp   2.799e-12   2.476e-12   3.100e-12
| Where nom  PVT is Nominal Process,  3.3V,  25C
|   Fast PVT is Strong Process,   3.6V,  -40C
|   Slow PVT is Weak Process,   3V,  85C
[Model Spec]
Vinl   0.66   0.6   0.72
Vinh   2.64   2.4   2.88
[Voltage Range]   3.3   3   3.6
|Ambient Temperature   25   85   -40
|Junction Temperature
[Temperature Range]   25   85   -40
[Pullup Reference]   3.3   3   3.6
[Pulldown Reference]   0   0   0
[Power Clamp Reference]   3.3   3   3.6
[GND Clamp Reference]   0   0   0
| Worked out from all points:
|   slope of the pulldown table from 0 to 0.495 V, typ, clamps not added: 43.1 ohm
|   slope of the pullup table from 0 to 0.495 V, typ, clamps not added: 43.1 ohm
|   GND clamp passes 1 mA (typ) near -0.61 V on its own axis
|   POWER clamp passes 1 mA (typ) near -0.81 V on its own axis
|   falling waveform, V_fixture 3.3V, R_fixture 50Ohm: 20-80 % time 378ps typ, 527ps min, 265ps max; typ from 3.3 V to 1.88 V
|   rising waveform, V_fixture 0V, R_fixture 50Ohm: 20-80 % time 322ps typ, 470ps min, 216ps max; typ from 0 V to 1.53 V
|   rising waveform, V_fixture 3.3V, R_fixture 50Ohm: 20-80 % time 203ps typ, 290ps min, 143ps max; typ from 1.88 V to 3.3 V
|   falling waveform, V_fixture 0V, R_fixture 50Ohm: 20-80 % time 209ps typ, 337ps min, 136ps max; typ from 1.54 V to 0.004 V
[Pulldown]
|   Voltage   I(typ)   I(min)   I(max)
-3.3V     -85.76mA   -54.7mA    -115.8mA
172.8mV   4.34mA     2.512mA    5.975mA
651.6mV   14.72mA    9.067mA    20.52mA
939.6mV   19.77mA    11.85mA    27.79mA
1.246V    24.05mA    13.85mA    34.24mA
1.573V    27.13mA    15.32mA    39.48mA
1.814V    27.9mA     15.71mA    41.49mA
2.012V    28.53mA    15.91mA    42.2mA
2.627V    29.47mA    16.25mA    43.08mA
4.5V      30.27mA    16.64mA    44.23mA
6.6V      32.15mA    17.33mA    46.89mA
[GND Clamp]
|   Voltage   I(typ)   I(min)   I(max)
-3.3V     -490.9mA   -343.8mA   -691.8mA
-1.184V   -60.31mA   -43.57mA   -85.99mA
-1.062V   -40.36mA   -30.8mA    -54.53mA
-1.02V    -33.49mA   -27.17mA   -44.91mA
-968.4mV  -26.64mA   -22.76mA   -33.41mA
-896.4mV  -17.05mA   -16.58mA   -21.47mA
-817.2mV  -9.309mA   -10.59mA   -13.23mA
-745.8mV  -4.661mA   -5.895mA   -8.067mA
-699mV    -3.403mA   -3.171mA   -5.14mA
-612mV    -1.063mA   -630.7uA   -1.443mA
-543mV    -200.9uA   -137.6uA   -360.6uA
6.6V      0A         0A         0A
[Pullup]
|   Voltage   I(typ)   I(min)   I(max)
-3.3V     83.84mA    59.35mA    117.5mA
172.8mV   -4.272mA   -2.827mA   -6.008mA
583.2mV   -13.38mA   -9.324mA   -18.99mA
939.6mV   -20.19mA   -13.7mA    -28.71mA
1.246V    -24.99mA   -16.53mA   -35.81mA
1.588V    -29.1mA    -18.97mA   -42.32mA
2.167V    -33.36mA   -20.84mA   -49.72mA
3.089V    -36.92mA   -22.65mA   -55.5mA
4.496V    -40.34mA   -24.57mA   -59.74mA
6.6V      -43.54mA   -26.68mA   -63.12mA
[POWER Clamp]
|   Voltage   I(typ)   I(min)   I(max)
-3.3V     146.2mA    134.9mA    163mA
-1.433V   57mA       52.61mA    64.51mA
-1.03V    17.02mA    20.65mA    11.29mA
-896.4mV  5.124mA    10.1mA     846.5uA
-871.2mV  3.418mA    8.34mA     451.8uA
-844.8mV  2.002mA    6.571mA    276.8uA
-825mV    1.23mA     5.313mA    170.9uA
-792mV    473uA      3.472mA    78.97uA
-753mV    138.9uA    1.78mA     31.29uA
-702mV    29.02uA    535.9uA    7.468uA
-591mV    2.7uA      19.47uA    3.289uA
6.6V      0A         0A         0A
[Ramp]
R_load = 50
|   typ   min   max
dV/dt_r   0.920374/3.21317e-10   0.606654/4.68706e-10   1.24134/2.1518e-10
dV/dt_f   0.850982/3.7798e-10   0.477251/5.19248e-10   1.19508/2.64213e-10
[Falling Waveform]
V_fixture = 3.3V
V_fixture_min = 3V
V_fixture_max = 3.6V
R_fixture = 50Ohm
|   Time   V(typ)   V(min)   V(max)
0s        3.3V       3V         3.6V
303.5ps   3.302V     3V         3.572V
382ps     3.318V     2.999V     3.284V
468.5ps   3.318V     2.999V     2.751V
595ps     3.112V     3.005V     2.185V
723.5ps   2.716V     3.02V      1.887V
883ps     2.339V     3.021V     1.715V
1.222ns   2.002V     2.684V     1.625V
1.688ns   1.903V     2.333V     1.613V
2.999ns   1.882V     2.205V     1.608V
[Rising Waveform]
V_fixture = 0V
V_fixture_min = 0V
V_fixture_max = 0V
R_fixture = 50Ohm
|   Time   V(typ)   V(min)   V(max)
0s        1.005nV    1.171nV    905.5pV
320ps     -1.728mV   318.5uV    56.48mV
395ps     -8.175mV   518.1uV    346.9mV
510ps     57.23mV    107.4uV    1.16V
586ps     215.8mV    -1.292mV   1.54V
829.5ps   1.025V     3.779mV    1.97V
1.097ns   1.384V     271.8mV    2.05V
1.35ns    1.484V     658.1mV    2.061V
1.62ns    1.516V     864.8mV    2.064V
2.999ns   1.534V     1.011V     2.069V
[Rising Waveform]
V_fixture = 3.3V
V_fixture_min = 3V
V_fixture_max = 3.6V
R_fixture = 50Ohm
|   Time   V(typ)   V(min)   V(max)
0s        1.876V     2.197V     1.606V
295.5ps   1.871V     2.198V     1.665V
338.5ps   1.866V     2.198V     1.909V
436ps     1.899V     2.197V     2.844V
487.5ps   2.017V     2.195V     3.174V
670ps     2.848V     2.181V     3.522V
867ps     3.189V     2.31V      3.585V
1.134ns   3.275V     2.787V     3.595V
1.314ns   3.289V     2.914V     3.596V
2.999ns   3.298V     2.998V     3.599V
[Falling Waveform]
V_fixture = 0V
V_fixture_min = 0V
V_fixture_max = 0V
R_fixture = 50Ohm
|   Time   V(typ)   V(min)   V(max)
0s        1.54V      1.022V     2.068V
258ps     1.543V     1.022V     2.022V
307.5ps   1.538V     1.023V     1.74V
387ps     1.467V     1.026V     874.6mV
445ps     1.31V      1.029V     449.8mV
622ps     462mV      991.4mV    87.43mV
811ps     119.8mV    709.5mV    22.52mV
1.035ns   36.96mV    273.2mV    8.463mV
1.283ns   14.08mV    89.34mV    6.156mV
2.999ns   4.166mV    5.22mV     1.668mV
